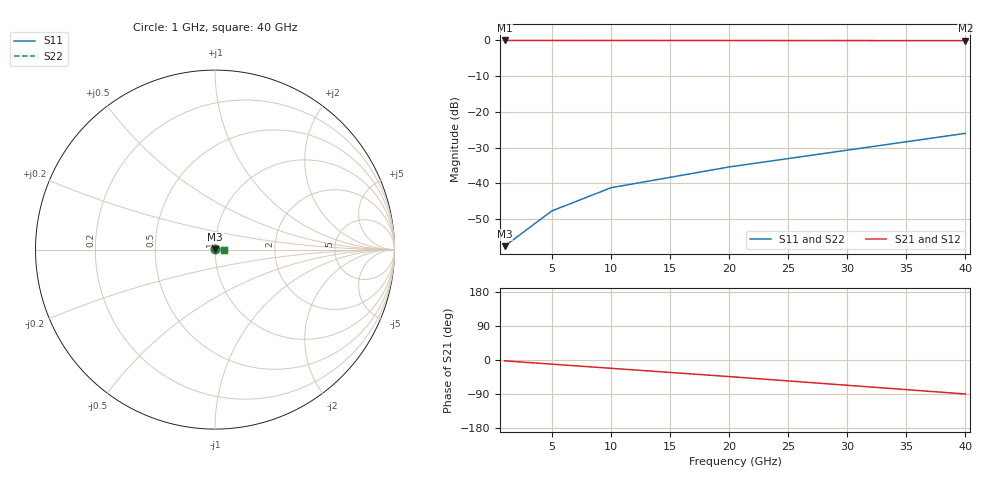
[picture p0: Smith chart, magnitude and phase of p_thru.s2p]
! Generated by circuitRF - EM: Full-wave planar
! circuitRF-EM setup: p_thru
! circuitRF-EM layout: thru/layout/thru.clay
! circuitRF-EM written: 2026-11-04 22:58:26Z
! circuitRF-EM geometry: 05bdcd56bbb3613d
! circuitRF-EM mesh: 025622186bca0020
! circuitRF-EM ports: 5bce169309c672a4
! circuitRF-EM model: grounded-edge-port-2026-10-14
! Port[1] = 1
! Port[2] = 2
! circuitRF-EM port 1: '1' at (0, 0 um), edge, de-embedded, 50 Ohm
! circuitRF-EM port 2: '2' at (640, 0 um), edge, de-embedded, 50 Ohm
! circuitRF-EM: port N of this file is the label named on the 'port N' line above. A circuit that composes this result binds its nets in that order; two ports of a reciprocal part swapped gives a plausible curve of a different structure.
! circuitRF-EM: re-running the EM setup rewrites this file. If circuitRF reports it as stale, the layout's cross-section changed after this file was written.
# GHz S RI R 50
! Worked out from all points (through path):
!   5 points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, 1 GHz to 40 GHz, reference 50 ohm
!   highest |S21| = -0.01 dB at 1 GHz (marker M1); lowest = -0.1 dB at 40 GHz (marker M2)
!   lowest |S11| = -57.5 dB at 1 GHz (marker M3), VSWR 1.00, Z = 50.1 + j0.0669 ohm
!   |S11| at or under -10 dB: start of sweep to end of sweep
!   |S22| runs from -57.5 to -26.0 dB; largest |S21 - S12| = 2.6e-09
1  0.00115 0.000668  0.9982 -0.0382  0.9982 -0.0382  0.00115 0.000668
5  0.00212 0.00354  0.9804 -0.1899  0.9804 -0.1899  0.00212 0.00354
10  0.00507 0.00709  0.926 -0.3724  0.926 -0.3724  0.00507 0.00709
20  0.0137 0.01  0.7209 -0.6896  0.7209 -0.6896  0.0137 0.01
40  0.0501 -0.00355  0.00585 -0.9927  0.00585 -0.9927  0.0501 -0.00375
